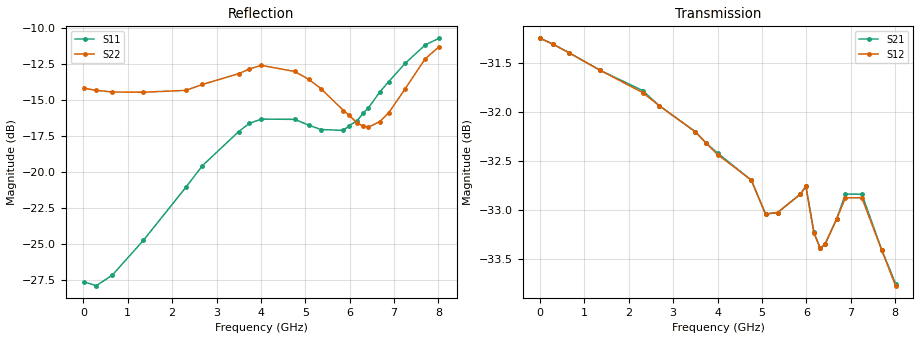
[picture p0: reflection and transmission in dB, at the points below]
! DEVICE ID: PE43712
! File Path: z:\PE43713\PE43713_CHAR_NOM_04292014\AMB\3p300\LS_ATT_30p00dB\PE43713_AMB_3p300V_3p000V_0p000V_LS_ATT_30p00dB_S2P_SN_10_A0139A.s2p
! Serial: 10
! Lot: A0139A
! Temp: 25C
! VDD: 3.300
! VSS: 0.000
! Control_Hi: 3.000
! Control_Lo: 0.000
! Attenuation Step: 30.00dB
! Port 1: RF1
! Port 2: RF2
! ThroughPath:1-2
! IDD: 0.0001455668
! ISS: -4.73e-008
#  Hz  S  RI  R  50
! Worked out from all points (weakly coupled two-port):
!   801 points, 10 MHz to 8.01 GHz, reference 50 ohm
!   highest |S21| = -31.26 dB at 10 MHz (marker M1); lowest = -33.8 dB at 8.01 GHz (marker M2)
!   lowest |S11| = -27.9 dB at 290 MHz (marker M3), VSWR 1.08, Z = 46.3 + j1.23 ohm
!   |S11| at or under -10 dB: start of sweep to end of sweep
!   |S22| runs from -16.9 to -11.3 dB; largest |S21 - S12| = 0.00011
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1e7  -0.0416 0.000883  0.0274 -0.000118  0.0274 -0.000106  -0.1958 0.00128
2.9e8  -0.0381 0.0133  0.0271 -0.0025  0.0271 -0.0025  -0.1916 0.02
6.5e8  -0.0337 0.0281  0.0264 -0.00538  0.0264 -0.00538  -0.1852 0.0426
1.35e9  -0.021 0.054  0.0243 -0.0103  0.0243 -0.0103  -0.1702 0.0837
2.31e9  0.0103 0.0881  0.0202 -0.016  0.0202 -0.0159  -0.1334 0.1388
2.68e9  0.025 0.1023  0.0182 -0.0176  0.0182 -0.0176  -0.1163 0.1649
3.5e9  0.0484 0.1298  0.0135 -0.0205  0.0135 -0.0205  -0.0894 0.2011
3.74e9  0.0533 0.1379  0.0119 -0.0211  0.0119 -0.0211  -0.0859 0.2117
4.01e9  0.0582 0.1415  0.0103 -0.0216  0.0102 -0.0216  -0.0837 0.2197
4.76e9  0.0722 0.1345  0.00598 -0.0224  0.00601 -0.0224  -0.0655 0.2142
5.08e9  0.0816 0.1207  0.0041 -0.0219  0.00411 -0.0219  -0.056 0.2026
5.35e9  0.0911 0.1073  0.00312 -0.0221  0.00312 -0.0221  -0.0467 0.1897
5.86e9  0.1172 0.0762  0.000378 -0.0228  0.000401 -0.0228  -0.00754 0.1637
5.99e9  0.1269 0.0704  -0.000907 -0.023  -0.000856 -0.023  0.0051 0.1575
6.17e9  0.1386 0.0602  -0.00213 -0.0217  -0.00208 -0.0217  0.0246 0.1461
6.31e9  0.1514 0.0546  -0.00209 -0.0213  -0.00207 -0.0213  0.0425 0.1382
6.42e9  0.1594 0.0507  -0.00211 -0.0214  -0.00208 -0.0214  0.0559 0.132
6.68e9  0.1852 0.0435  -0.0033 -0.0219  -0.00329 -0.0219  0.0889 0.1209
6.88e9  0.2028 0.0386  -0.00481 -0.0223  -0.00479 -0.0222  0.1111 0.1164
7.25e9  0.2365 0.0349  -0.00789 -0.0214  -0.00789 -0.0213  0.1559 0.117
7.7e9  0.274 0.0391  -0.00956 -0.0191  -0.00953 -0.0191  0.2116 0.1288
8.01e9  0.2886 0.0433  -0.0104 -0.0177  -0.0103 -0.0177  0.2369 0.1349
